VERSION 5.8 ;
BUSBITCHARS "[]" ;
DIVIDERCHAR "/" ;
CLEARANCEMEASURE EUCLIDEAN ;

SITE coresite_DH_P
    SIZE 0.0450 BY 0.2880 ;
    CLASS CORE ;
    SYMMETRY X Y ;
END coresite_DH_P

SITE coresite_DH_N
    SIZE 0.0450 BY 0.2880 ;
    CLASS CORE ;
    SYMMETRY X Y ;
END coresite_DH_N

SITE coresite
    SIZE 0.0450 BY 0.1440 ;
    CLASS CORE ;
    SYMMETRY X Y ;
END coresite

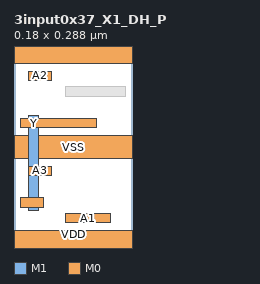
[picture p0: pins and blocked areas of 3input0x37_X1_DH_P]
MACRO 3input0x37_X1_DH_P
  CLASS CORE ;
  ORIGIN 0 0 ;
  FOREIGN 3input0x37_X1_DH_P 0 0 ;
  SIZE 0.1800 BY 0.2880 ;
  SYMMETRY X Y ;
  SITE coresite_DH_P ;
  PIN Y
    DIRECTION OUTPUT ;
    USE SIGNAL ;
    PORT
      LAYER M1 ;
        RECT 0.0225 0.1920 0.0375 0.0480 ;
      LAYER M0 ;
        RECT 0.0105 0.0670 0.0450 0.0530 ;
        RECT 0.0105 0.1870 0.1245 0.1730 ;
    END
  END Y
  PIN A1
    DIRECTION INPUT ;
    USE SIGNAL ;
    PORT
      LAYER M0 ;
        RECT 0.0780 0.0430 0.1470 0.0290 ;
    END
  END A1
  PIN A3
    DIRECTION INPUT ;
    USE SIGNAL ;
    PORT
      LAYER M0 ;
        RECT 0.0225 0.1150 0.0570 0.1010 ;
    END
  END A3
  PIN A2
    DIRECTION INPUT ;
    USE SIGNAL ;
    PORT
      LAYER M0 ;
        RECT 0.0225 0.2590 0.0570 0.2450 ;
    END
  END A2
  PIN VDD
    DIRECTION INOUT ;
    USE POWER ;
    SHAPE ABUTMENT ;
    PORT
      LAYER M0 ;
        RECT 0.0000 -0.0180 0.1800 0.0180 ;
        RECT 0.0000 0.2700 0.1800 0.3060 ;
    END
  END VDD
  PIN VSS
    DIRECTION INOUT ;
    USE GROUND ;
    SHAPE ABUTMENT ;
    PORT
      LAYER M0 ;
        RECT 0.0000 0.1260 0.1800 0.1620 ;
    END
  END VSS
  OBS
      LAYER M0 ;
        RECT 0.0780 0.2210 0.1695 0.2350 ;
      LAYER V0 ;
        RECT 0.0230 0.0530 0.0370 0.0670 ;
        RECT 0.0230 0.1730 0.0370 0.1870 ;
  END
END 3input0x37_X1_DH_P

END LIBRARY
